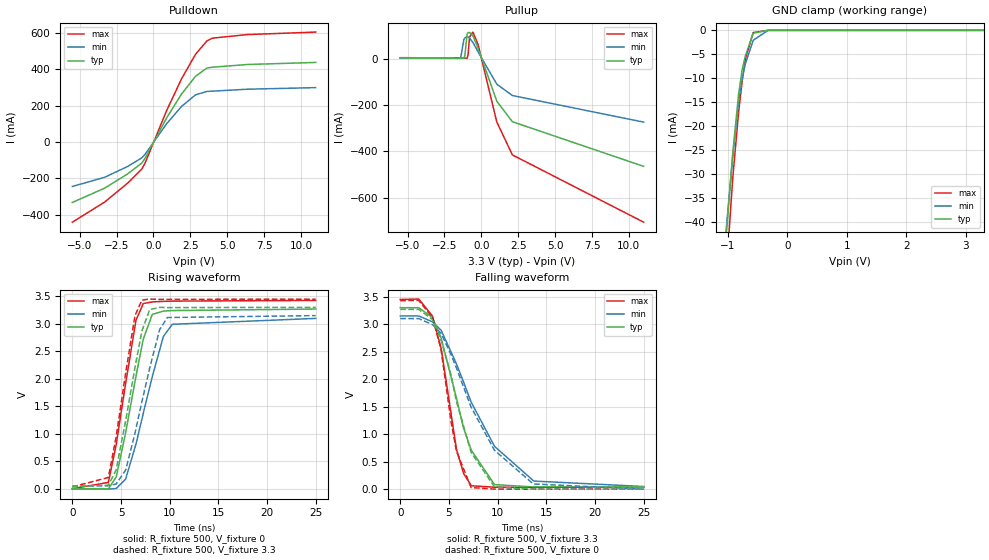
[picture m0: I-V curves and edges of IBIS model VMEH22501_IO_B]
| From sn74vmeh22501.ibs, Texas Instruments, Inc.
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[Model]   VMEH22501_IO_B
Model_type  I/O
Vinh =   1.7
Vinl =   1.6
Enable   Active-Low
Vref =   0
Rref =   500
Cref =   50p
Vmeas =   1.5
| variable   typ   min   max
C_comp   10.23pF   9.61pF   11.37pF
| C_pullup   28.07pF   12.02pF   54.82pF
| C_pulldown   12.87pF   9.52pF   16.27pF
| C_tri-state   10.23pF   9.61pF   11.37pF
[Temperature Range]   40   100   0
| Ambient temperature   25   85   0
[Voltage range]   3.3   3.15   3.45
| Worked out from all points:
|   slope of the pulldown table from 0 to 0.495 V, typ, clamps not added: 6.54 ohm
|   slope of the pullup table from 0 to 0.495 V, typ, clamps not added: 5.03 ohm
|   GND clamp passes 1 mA (typ) near -0.60 V on its own axis
|   rising waveform, R_fixture 500, V_fixture 0: 20-80 % time 2.07ns typ, 2.59ns min, 1.82ns max; typ from 0 V to 3.27 V
|   falling waveform, R_fixture 500, V_fixture 3.3: 20-80 % time 2.94ns typ, 5.01ns min, 1.84ns max; typ from 3.3 V to 0.04 V
|   rising waveform, R_fixture 500, V_fixture 3.3: 20-80 % time 1.98ns typ, 2.41ns min, 1.77ns max; typ from 0.04 V to 3.3 V
|   falling waveform, R_fixture 500, V_fixture 0: 20-80 % time 2.94ns typ, 4.94ns min, 1.84ns max; typ from 3.27 V to 0 V
[GND Clamp]
| VMEH22501_IO_B
|   Voltage   I(typ)   I(min)   I(max)
-5.5V     -906.2mA   -787.6mA   -1.055A
-1.165V   -65.88mA   -61.35mA   -77.74mA
-1.14V    -61.55mA   -57.61mA   -72.67mA
-1.105V   -55.56mA   -52.42mA   -65.66mA
-1.075V   -50.49mA   -48.04mA   -59.74mA
-920mV    -25.91mA   -26.62mA   -31.16mA
-820mV    -13.34mA   -15mA      -17.12mA
-760mV    -8.243mA   -9.962mA   -10.69mA
-705mV    -5.308mA   -6.938mA   -5.973mA
-575mV    -606.8uA   -2.078mA   -468.8uA
-325mV    -628.4nA   -12.08uA   -397.9nA
3.3V      144.4pA    15.27nA    -3.489nA
[Pulldown]
| VMEH22501_IO_B
|   Voltage   I(typ)   I(min)   I(max)
-5.5V     -333.1mA   -244.9mA   -441.7mA
-3.315V   -254.4mA   -194.5mA   -331.2mA
-1.755V   -176.1mA   -134.9mA   -226.9mA
-785mV    -115.4mA   -87mA      -148.4mA
-575mV    -90.54mA   -68.32mA   -117.3mA
890mV     132.5mA    100.3mA    172.6mA
1.9V      264mA      195.7mA    347.5mA
2.85V     361.7mA    259.9mA    482.9mA
3.625V    407.7mA    278.7mA    557.2mA
3.995V    411.9mA    280.1mA    572mA
6.35V     426.9mA    290.8mA    591.8mA
11V       438.3mA    299.6mA    605.5mA
[Pullup]
| VMEH22501_IO_B
|   Voltage   I(typ)   I(min)   I(max)
-5.5V     4.043mA    3.022mA    5.145mA
-1.41V    2.882mA    2.3mA      3.583mA
-1.185V   2.699mA    83.77mA    3.172mA
-1.12V    12.73mA    90.4mA     3.063mA
-970mV    106.7mA    95.96mA    2.974mA
-905mV    113.3mA    94.87mA    14.86mA
-800mV    113.8mA    89.14mA    94.22mA
-575mV    99.56mA    70.79mA    115.5mA
-225mV    46.57mA    30.03mA    62.32mA
1.045V    -182.9mA   -109.4mA   -272.6mA
2.1V      -271.4mA   -158.3mA   -414.6mA
11V       -464.2mA   -273.2mA   -705.2mA
[Ramp]
| VMEH22501_IO_B
| variable   typ   min   max
dV/dt_r   1.97/2.10E-09   1.86/2.61E-09   2.06/1.84E-09
dV/dt_f   1.96/2.97E-09   1.87/5.02E-09   2.05/1.87E-09
R_load = 500
[Rising Waveform]
| VMEH22501_IO_B
R_fixture =   500
C_fixture =   0
L_fixture =   0
V_fixture =   0
V_fixture_min = 0
V_fixture_max = 0
|   Time   V(typ)   V(min)   V(max)
0s        233.4uV    1.15uV     793.7uV
3.7ns     -4.451mV   -8.859mV   113.3mV
4.51ns    213.4mV    3.611mV    805.3mV
5.47ns    1.015V     173.6mV    1.914V
6.54ns    2.052V     814.4mV    3.068V
7.285ns   2.721V     1.373V     3.369V
8.21ns    3.172V     2.04V      3.399V
9.345ns   3.232V     2.77V      3.409V
10.27ns   3.242V     2.992V     3.414V
24.99ns   3.269V     3.099V     3.426V
[Falling Waveform]
| VMEH22501_IO_B
R_fixture =   500
C_fixture =   0
L_fixture =   0
V_fixture =   3.3
V_fixture_min = 3.15
V_fixture_max = 3.45
|   Time   V(typ)   V(min)   V(max)
0s        3.3V       3.15V      3.449V
1.9ns     3.3V       3.149V     3.457V
3.31ns    3.12V      3.043V     3.148V
4.205ns   2.746V     2.887V     2.559V
5.775ns   1.653V     2.277V     722.5mV
6.515ns   1.103V     1.941V     281.7mV
7.295ns   708.5mV    1.577V     62.41mV
9.68ns    83.12mV    778.5mV    35.26mV
13.71ns   40.6mV     147.6mV    33.25mV
24.99ns   39.69mV    48.53mV    32.99mV
[Rising Waveform]
| VMEH22501_IO_B
R_fixture =   500
C_fixture =   0
L_fixture =   0
V_fixture =   3.3
V_fixture_min = 3.15
V_fixture_max = 3.45
|   Time   V(typ)   V(min)   V(max)
0s        39.67mV    48.23mV    32.99mV
3.695ns   62.88mV    53.32mV    203.7mV
4.49ns    335.9mV    83.95mV    935.7mV
5.47ns    1.232V     338.2mV    2.097V
6.43ns    2.203V     1.004V     3.148V
7.14ns    2.868V     1.581V     3.432V
7.935ns   3.257V     2.189V     3.451V
8.965ns   3.3V       2.897V     3.445V
9.755ns   3.296V     3.115V     3.446V
24.99ns   3.3V       3.15V      3.449V
[Falling Waveform]
| VMEH22501_IO_B
R_fixture =   500
C_fixture =   0
L_fixture =   0
V_fixture =   0
V_fixture_min = 0
V_fixture_max = 0
|   Time   V(typ)   V(min)   V(max)
0s        3.27V      3.103V     3.427V
1.9ns     3.269V     3.102V     3.434V
3.305ns   3.086V     2.992V     3.122V
4.2ns     2.706V     2.832V     2.53V
5.22ns    2.067V     2.443V     1.222V
5.775ns   1.592V     2.203V     689.9mV
7.275ns   670.5mV    1.493V     29.81mV
9.665ns   42.63mV    708.9mV    1.274mV
13.66ns   701.1uV    94.86mV    803.8uV
24.99ns   246uV      226.2uV    796uV
